##
## LEF for PtnCells ;
## created by Innovus v15.23-s045_1 on Wed Mar  4 17:17:28 2026
##

VERSION 5.8 ;

BUSBITCHARS "[]" ;
DIVIDERCHAR "/" ;

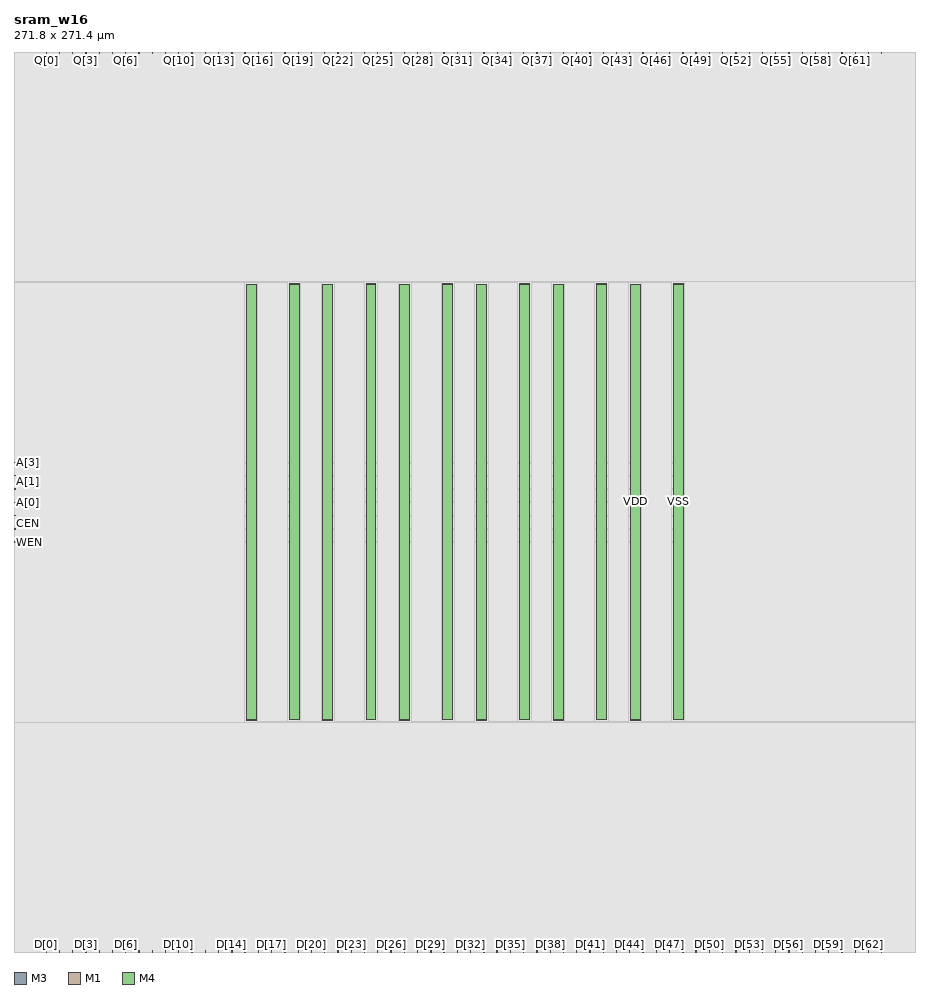
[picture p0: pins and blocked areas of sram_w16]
MACRO sram_w16
  CLASS BLOCK ;
  SIZE 271.8000 BY 271.4000 ;
  FOREIGN sram_w16 0.0000 0.0000 ;
  ORIGIN 0 0 ;
  SYMMETRY X Y R90 ;
  PIN CLK
    DIRECTION INPUT ;
    USE SIGNAL ;
    PORT
      LAYER M3 ;
        RECT 0.0000 127.5500 0.5200 127.6500 ;
    END
  END CLK
  PIN D[63]
    DIRECTION INPUT ;
    USE SIGNAL ;
    PORT
      LAYER M1 ;
        RECT 261.6500 0.0000 261.7500 0.5200 ;
    END
  END D[63]
  PIN D[62]
    DIRECTION INPUT ;
    USE SIGNAL ;
    PORT
      LAYER M1 ;
        RECT 257.6500 0.0000 257.7500 0.5200 ;
    END
  END D[62]
  PIN D[61]
    DIRECTION INPUT ;
    USE SIGNAL ;
    PORT
      LAYER M1 ;
        RECT 253.6500 0.0000 253.7500 0.5200 ;
    END
  END D[61]
  PIN D[60]
    DIRECTION INPUT ;
    USE SIGNAL ;
    PORT
      LAYER M1 ;
        RECT 249.6500 0.0000 249.7500 0.5200 ;
    END
  END D[60]
  PIN D[59]
    DIRECTION INPUT ;
    USE SIGNAL ;
    PORT
      LAYER M1 ;
        RECT 245.6500 0.0000 245.7500 0.5200 ;
    END
  END D[59]
  PIN D[58]
    DIRECTION INPUT ;
    USE SIGNAL ;
    PORT
      LAYER M1 ;
        RECT 241.6500 0.0000 241.7500 0.5200 ;
    END
  END D[58]
  PIN D[57]
    DIRECTION INPUT ;
    USE SIGNAL ;
    PORT
      LAYER M1 ;
        RECT 237.6500 0.0000 237.7500 0.5200 ;
    END
  END D[57]
  PIN D[56]
    DIRECTION INPUT ;
    USE SIGNAL ;
    PORT
      LAYER M1 ;
        RECT 233.6500 0.0000 233.7500 0.5200 ;
    END
  END D[56]
  PIN D[55]
    DIRECTION INPUT ;
    USE SIGNAL ;
    PORT
      LAYER M1 ;
        RECT 229.6500 0.0000 229.7500 0.5200 ;
    END
  END D[55]
  PIN D[54]
    DIRECTION INPUT ;
    USE SIGNAL ;
    PORT
      LAYER M1 ;
        RECT 225.6500 0.0000 225.7500 0.5200 ;
    END
  END D[54]
  PIN D[53]
    DIRECTION INPUT ;
    USE SIGNAL ;
    PORT
      LAYER M1 ;
        RECT 221.6500 0.0000 221.7500 0.5200 ;
    END
  END D[53]
  PIN D[52]
    DIRECTION INPUT ;
    USE SIGNAL ;
    PORT
      LAYER M1 ;
        RECT 217.6500 0.0000 217.7500 0.5200 ;
    END
  END D[52]
  PIN D[51]
    DIRECTION INPUT ;
    USE SIGNAL ;
    PORT
      LAYER M1 ;
        RECT 213.6500 0.0000 213.7500 0.5200 ;
    END
  END D[51]
  PIN D[50]
    DIRECTION INPUT ;
    USE SIGNAL ;
    PORT
      LAYER M1 ;
        RECT 209.6500 0.0000 209.7500 0.5200 ;
    END
  END D[50]
  PIN D[49]
    DIRECTION INPUT ;
    USE SIGNAL ;
    PORT
      LAYER M1 ;
        RECT 205.6500 0.0000 205.7500 0.5200 ;
    END
  END D[49]
  PIN D[48]
    DIRECTION INPUT ;
    USE SIGNAL ;
    PORT
      LAYER M1 ;
        RECT 201.6500 0.0000 201.7500 0.5200 ;
    END
  END D[48]
  PIN D[47]
    DIRECTION INPUT ;
    USE SIGNAL ;
    PORT
      LAYER M1 ;
        RECT 197.6500 0.0000 197.7500 0.5200 ;
    END
  END D[47]
  PIN D[46]
    DIRECTION INPUT ;
    USE SIGNAL ;
    PORT
      LAYER M1 ;
        RECT 193.6500 0.0000 193.7500 0.5200 ;
    END
  END D[46]
  PIN D[45]
    DIRECTION INPUT ;
    USE SIGNAL ;
    PORT
      LAYER M1 ;
        RECT 189.6500 0.0000 189.7500 0.5200 ;
    END
  END D[45]
  PIN D[44]
    DIRECTION INPUT ;
    USE SIGNAL ;
    PORT
      LAYER M1 ;
        RECT 185.6500 0.0000 185.7500 0.5200 ;
    END
  END D[44]
  PIN D[43]
    DIRECTION INPUT ;
    USE SIGNAL ;
    PORT
      LAYER M1 ;
        RECT 181.6500 0.0000 181.7500 0.5200 ;
    END
  END D[43]
  PIN D[42]
    DIRECTION INPUT ;
    USE SIGNAL ;
    PORT
      LAYER M1 ;
        RECT 177.6500 0.0000 177.7500 0.5200 ;
    END
  END D[42]
  PIN D[41]
    DIRECTION INPUT ;
    USE SIGNAL ;
    PORT
      LAYER M1 ;
        RECT 173.6500 0.0000 173.7500 0.5200 ;
    END
  END D[41]
  PIN D[40]
    DIRECTION INPUT ;
    USE SIGNAL ;
    PORT
      LAYER M1 ;
        RECT 169.6500 0.0000 169.7500 0.5200 ;
    END
  END D[40]
  PIN D[39]
    DIRECTION INPUT ;
    USE SIGNAL ;
    PORT
      LAYER M1 ;
        RECT 165.6500 0.0000 165.7500 0.5200 ;
    END
  END D[39]
  PIN D[38]
    DIRECTION INPUT ;
    USE SIGNAL ;
    PORT
      LAYER M1 ;
        RECT 161.6500 0.0000 161.7500 0.5200 ;
    END
  END D[38]
  PIN D[37]
    DIRECTION INPUT ;
    USE SIGNAL ;
    PORT
      LAYER M1 ;
        RECT 157.6500 0.0000 157.7500 0.5200 ;
    END
  END D[37]
  PIN D[36]
    DIRECTION INPUT ;
    USE SIGNAL ;
    PORT
      LAYER M1 ;
        RECT 153.6500 0.0000 153.7500 0.5200 ;
    END
  END D[36]
  PIN D[35]
    DIRECTION INPUT ;
    USE SIGNAL ;
    PORT
      LAYER M1 ;
        RECT 149.6500 0.0000 149.7500 0.5200 ;
    END
  END D[35]
  PIN D[34]
    DIRECTION INPUT ;
    USE SIGNAL ;
    PORT
      LAYER M1 ;
        RECT 145.6500 0.0000 145.7500 0.5200 ;
    END
  END D[34]
  PIN D[33]
    DIRECTION INPUT ;
    USE SIGNAL ;
    PORT
      LAYER M1 ;
        RECT 141.6500 0.0000 141.7500 0.5200 ;
    END
  END D[33]
  PIN D[32]
    DIRECTION INPUT ;
    USE SIGNAL ;
    PORT
      LAYER M1 ;
        RECT 137.6500 0.0000 137.7500 0.5200 ;
    END
  END D[32]
  PIN D[31]
    DIRECTION INPUT ;
    USE SIGNAL ;
    PORT
      LAYER M1 ;
        RECT 133.6500 0.0000 133.7500 0.5200 ;
    END
  END D[31]
  PIN D[30]
    DIRECTION INPUT ;
    USE SIGNAL ;
    PORT
      LAYER M1 ;
        RECT 129.6500 0.0000 129.7500 0.5200 ;
    END
  END D[30]
  PIN D[29]
    DIRECTION INPUT ;
    USE SIGNAL ;
    PORT
      LAYER M1 ;
        RECT 125.6500 0.0000 125.7500 0.5200 ;
    END
  END D[29]
  PIN D[28]
    DIRECTION INPUT ;
    USE SIGNAL ;
    PORT
      LAYER M1 ;
        RECT 121.6500 0.0000 121.7500 0.5200 ;
    END
  END D[28]
  PIN D[27]
    DIRECTION INPUT ;
    USE SIGNAL ;
    PORT
      LAYER M1 ;
        RECT 117.6500 0.0000 117.7500 0.5200 ;
    END
  END D[27]
  PIN D[26]
    DIRECTION INPUT ;
    USE SIGNAL ;
    PORT
      LAYER M1 ;
        RECT 113.6500 0.0000 113.7500 0.5200 ;
    END
  END D[26]
  PIN D[25]
    DIRECTION INPUT ;
    USE SIGNAL ;
    PORT
      LAYER M1 ;
        RECT 109.6500 0.0000 109.7500 0.5200 ;
    END
  END D[25]
  PIN D[24]
    DIRECTION INPUT ;
    USE SIGNAL ;
    PORT
      LAYER M1 ;
        RECT 105.6500 0.0000 105.7500 0.5200 ;
    END
  END D[24]
  PIN D[23]
    DIRECTION INPUT ;
    USE SIGNAL ;
    PORT
      LAYER M1 ;
        RECT 101.6500 0.0000 101.7500 0.5200 ;
    END
  END D[23]
  PIN D[22]
    DIRECTION INPUT ;
    USE SIGNAL ;
    PORT
      LAYER M1 ;
        RECT 97.6500 0.0000 97.7500 0.5200 ;
    END
  END D[22]
  PIN D[21]
    DIRECTION INPUT ;
    USE SIGNAL ;
    PORT
      LAYER M1 ;
        RECT 93.6500 0.0000 93.7500 0.5200 ;
    END
  END D[21]
  PIN D[20]
    DIRECTION INPUT ;
    USE SIGNAL ;
    PORT
      LAYER M1 ;
        RECT 89.6500 0.0000 89.7500 0.5200 ;
    END
  END D[20]
  PIN D[19]
    DIRECTION INPUT ;
    USE SIGNAL ;
    PORT
      LAYER M1 ;
        RECT 85.6500 0.0000 85.7500 0.5200 ;
    END
  END D[19]
  PIN D[18]
    DIRECTION INPUT ;
    USE SIGNAL ;
    PORT
      LAYER M1 ;
        RECT 81.6500 0.0000 81.7500 0.5200 ;
    END
  END D[18]
  PIN D[17]
    DIRECTION INPUT ;
    USE SIGNAL ;
    PORT
      LAYER M1 ;
        RECT 77.6500 0.0000 77.7500 0.5200 ;
    END
  END D[17]
  PIN D[16]
    DIRECTION INPUT ;
    USE SIGNAL ;
    PORT
      LAYER M1 ;
        RECT 73.6500 0.0000 73.7500 0.5200 ;
    END
  END D[16]
  PIN D[15]
    DIRECTION INPUT ;
    USE SIGNAL ;
    PORT
      LAYER M1 ;
        RECT 69.6500 0.0000 69.7500 0.5200 ;
    END
  END D[15]
  PIN D[14]
    DIRECTION INPUT ;
    USE SIGNAL ;
    PORT
      LAYER M1 ;
        RECT 65.6500 0.0000 65.7500 0.5200 ;
    END
  END D[14]
  PIN D[13]
    DIRECTION INPUT ;
    USE SIGNAL ;
    PORT
      LAYER M1 ;
        RECT 61.6500 0.0000 61.7500 0.5200 ;
    END
  END D[13]
  PIN D[12]
    DIRECTION INPUT ;
    USE SIGNAL ;
    PORT
      LAYER M1 ;
        RECT 57.6500 0.0000 57.7500 0.5200 ;
    END
  END D[12]
  PIN D[11]
    DIRECTION INPUT ;
    USE SIGNAL ;
    PORT
      LAYER M1 ;
        RECT 53.6500 0.0000 53.7500 0.5200 ;
    END
  END D[11]
  PIN D[10]
    DIRECTION INPUT ;
    USE SIGNAL ;
    PORT
      LAYER M1 ;
        RECT 49.6500 0.0000 49.7500 0.5200 ;
    END
  END D[10]
  PIN D[9]
    DIRECTION INPUT ;
    USE SIGNAL ;
    PORT
      LAYER M1 ;
        RECT 45.6500 0.0000 45.7500 0.5200 ;
    END
  END D[9]
  PIN D[8]
    DIRECTION INPUT ;
    USE SIGNAL ;
    PORT
      LAYER M1 ;
        RECT 41.6500 0.0000 41.7500 0.5200 ;
    END
  END D[8]
  PIN D[7]
    DIRECTION INPUT ;
    USE SIGNAL ;
    PORT
      LAYER M1 ;
        RECT 37.6500 0.0000 37.7500 0.5200 ;
    END
  END D[7]
  PIN D[6]
    DIRECTION INPUT ;
    USE SIGNAL ;
    PORT
      LAYER M1 ;
        RECT 33.6500 0.0000 33.7500 0.5200 ;
    END
  END D[6]
  PIN D[5]
    DIRECTION INPUT ;
    USE SIGNAL ;
    PORT
      LAYER M1 ;
        RECT 29.6500 0.0000 29.7500 0.5200 ;
    END
  END D[5]
  PIN D[4]
    DIRECTION INPUT ;
    USE SIGNAL ;
    PORT
      LAYER M1 ;
        RECT 25.6500 0.0000 25.7500 0.5200 ;
    END
  END D[4]
  PIN D[3]
    DIRECTION INPUT ;
    USE SIGNAL ;
    PORT
      LAYER M1 ;
        RECT 21.6500 0.0000 21.7500 0.5200 ;
    END
  END D[3]
  PIN D[2]
    DIRECTION INPUT ;
    USE SIGNAL ;
    PORT
      LAYER M1 ;
        RECT 17.6500 0.0000 17.7500 0.5200 ;
    END
  END D[2]
  PIN D[1]
    DIRECTION INPUT ;
    USE SIGNAL ;
    PORT
      LAYER M1 ;
        RECT 13.6500 0.0000 13.7500 0.5200 ;
    END
  END D[1]
  PIN D[0]
    DIRECTION INPUT ;
    USE SIGNAL ;
    PORT
      LAYER M1 ;
        RECT 9.6500 0.0000 9.7500 0.5200 ;
    END
  END D[0]
  PIN Q[63]
    DIRECTION OUTPUT ;
    USE SIGNAL ;
    PORT
      LAYER M1 ;
        RECT 261.6550 270.9300 261.7450 271.4000 ;
    END
  END Q[63]
  PIN Q[62]
    DIRECTION OUTPUT ;
    USE SIGNAL ;
    PORT
      LAYER M1 ;
        RECT 257.6550 270.9300 257.7450 271.4000 ;
    END
  END Q[62]
  PIN Q[61]
    DIRECTION OUTPUT ;
    USE SIGNAL ;
    PORT
      LAYER M1 ;
        RECT 253.6550 270.9300 253.7450 271.4000 ;
    END
  END Q[61]
  PIN Q[60]
    DIRECTION OUTPUT ;
    USE SIGNAL ;
    PORT
      LAYER M1 ;
        RECT 249.6550 270.9300 249.7450 271.4000 ;
    END
  END Q[60]
  PIN Q[59]
    DIRECTION OUTPUT ;
    USE SIGNAL ;
    PORT
      LAYER M1 ;
        RECT 245.6550 270.9300 245.7450 271.4000 ;
    END
  END Q[59]
  PIN Q[58]
    DIRECTION OUTPUT ;
    USE SIGNAL ;
    PORT
      LAYER M1 ;
        RECT 241.6550 270.9300 241.7450 271.4000 ;
    END
  END Q[58]
  PIN Q[57]
    DIRECTION OUTPUT ;
    USE SIGNAL ;
    PORT
      LAYER M1 ;
        RECT 237.6550 270.9300 237.7450 271.4000 ;
    END
  END Q[57]
  PIN Q[56]
    DIRECTION OUTPUT ;
    USE SIGNAL ;
    PORT
      LAYER M1 ;
        RECT 233.6550 270.9300 233.7450 271.4000 ;
    END
  END Q[56]
  PIN Q[55]
    DIRECTION OUTPUT ;
    USE SIGNAL ;
    PORT
      LAYER M1 ;
        RECT 229.6550 270.9300 229.7450 271.4000 ;
    END
  END Q[55]
  PIN Q[54]
    DIRECTION OUTPUT ;
    USE SIGNAL ;
    PORT
      LAYER M1 ;
        RECT 225.6550 270.9300 225.7450 271.4000 ;
    END
  END Q[54]
  PIN Q[53]
    DIRECTION OUTPUT ;
    USE SIGNAL ;
    PORT
      LAYER M1 ;
        RECT 221.6550 270.9300 221.7450 271.4000 ;
    END
  END Q[53]
  PIN Q[52]
    DIRECTION OUTPUT ;
    USE SIGNAL ;
    PORT
      LAYER M1 ;
        RECT 217.6550 270.9300 217.7450 271.4000 ;
    END
  END Q[52]
  PIN Q[51]
    DIRECTION OUTPUT ;
    USE SIGNAL ;
    PORT
      LAYER M1 ;
        RECT 213.6550 270.9300 213.7450 271.4000 ;
    END
  END Q[51]
  PIN Q[50]
    DIRECTION OUTPUT ;
    USE SIGNAL ;
    PORT
      LAYER M1 ;
        RECT 209.6550 270.9300 209.7450 271.4000 ;
    END
  END Q[50]
  PIN Q[49]
    DIRECTION OUTPUT ;
    USE SIGNAL ;
    PORT
      LAYER M1 ;
        RECT 205.6550 270.9300 205.7450 271.4000 ;
    END
  END Q[49]
  PIN Q[48]
    DIRECTION OUTPUT ;
    USE SIGNAL ;
    PORT
      LAYER M1 ;
        RECT 201.6550 270.9300 201.7450 271.4000 ;
    END
  END Q[48]
  PIN Q[47]
    DIRECTION OUTPUT ;
    USE SIGNAL ;
    PORT
      LAYER M1 ;
        RECT 197.6550 270.9300 197.7450 271.4000 ;
    END
  END Q[47]
  PIN Q[46]
    DIRECTION OUTPUT ;
    USE SIGNAL ;
    PORT
      LAYER M1 ;
        RECT 193.6550 270.9300 193.7450 271.4000 ;
    END
  END Q[46]
  PIN Q[45]
    DIRECTION OUTPUT ;
    USE SIGNAL ;
    PORT
      LAYER M1 ;
        RECT 189.6550 270.9300 189.7450 271.4000 ;
    END
  END Q[45]
  PIN Q[44]
    DIRECTION OUTPUT ;
    USE SIGNAL ;
    PORT
      LAYER M1 ;
        RECT 185.6550 270.9300 185.7450 271.4000 ;
    END
  END Q[44]
  PIN Q[43]
    DIRECTION OUTPUT ;
    USE SIGNAL ;
    PORT
      LAYER M1 ;
        RECT 181.6550 270.9300 181.7450 271.4000 ;
    END
  END Q[43]
  PIN Q[42]
    DIRECTION OUTPUT ;
    USE SIGNAL ;
    PORT
      LAYER M1 ;
        RECT 177.6550 270.9300 177.7450 271.4000 ;
    END
  END Q[42]
  PIN Q[41]
    DIRECTION OUTPUT ;
    USE SIGNAL ;
    PORT
      LAYER M1 ;
        RECT 173.6550 270.9300 173.7450 271.4000 ;
    END
  END Q[41]
  PIN Q[40]
    DIRECTION OUTPUT ;
    USE SIGNAL ;
    PORT
      LAYER M1 ;
        RECT 169.6550 270.9300 169.7450 271.4000 ;
    END
  END Q[40]
  PIN Q[39]
    DIRECTION OUTPUT ;
    USE SIGNAL ;
    PORT
      LAYER M1 ;
        RECT 165.6550 270.9300 165.7450 271.4000 ;
    END
  END Q[39]
  PIN Q[38]
    DIRECTION OUTPUT ;
    USE SIGNAL ;
    PORT
      LAYER M1 ;
        RECT 161.6550 270.9300 161.7450 271.4000 ;
    END
  END Q[38]
  PIN Q[37]
    DIRECTION OUTPUT ;
    USE SIGNAL ;
    PORT
      LAYER M1 ;
        RECT 157.6550 270.9300 157.7450 271.4000 ;
    END
  END Q[37]
  PIN Q[36]
    DIRECTION OUTPUT ;
    USE SIGNAL ;
    PORT
      LAYER M1 ;
        RECT 153.6550 270.9300 153.7450 271.4000 ;
    END
  END Q[36]
  PIN Q[35]
    DIRECTION OUTPUT ;
    USE SIGNAL ;
    PORT
      LAYER M1 ;
        RECT 149.6550 270.9300 149.7450 271.4000 ;
    END
  END Q[35]
  PIN Q[34]
    DIRECTION OUTPUT ;
    USE SIGNAL ;
    PORT
      LAYER M1 ;
        RECT 145.6550 270.9300 145.7450 271.4000 ;
    END
  END Q[34]
  PIN Q[33]
    DIRECTION OUTPUT ;
    USE SIGNAL ;
    PORT
      LAYER M1 ;
        RECT 141.6550 270.9300 141.7450 271.4000 ;
    END
  END Q[33]
  PIN Q[32]
    DIRECTION OUTPUT ;
    USE SIGNAL ;
    PORT
      LAYER M1 ;
        RECT 137.6550 270.9300 137.7450 271.4000 ;
    END
  END Q[32]
  PIN Q[31]
    DIRECTION OUTPUT ;
    USE SIGNAL ;
    PORT
      LAYER M1 ;
        RECT 133.6550 270.9300 133.7450 271.4000 ;
    END
  END Q[31]
  PIN Q[30]
    DIRECTION OUTPUT ;
    USE SIGNAL ;
    PORT
      LAYER M1 ;
        RECT 129.6550 270.9300 129.7450 271.4000 ;
    END
  END Q[30]
  PIN Q[29]
    DIRECTION OUTPUT ;
    USE SIGNAL ;
    PORT
      LAYER M1 ;
        RECT 125.6550 270.9300 125.7450 271.4000 ;
    END
  END Q[29]
  PIN Q[28]
    DIRECTION OUTPUT ;
    USE SIGNAL ;
    PORT
      LAYER M1 ;
        RECT 121.6550 270.9300 121.7450 271.4000 ;
    END
  END Q[28]
  PIN Q[27]
    DIRECTION OUTPUT ;
    USE SIGNAL ;
    PORT
      LAYER M1 ;
        RECT 117.6550 270.9300 117.7450 271.4000 ;
    END
  END Q[27]
  PIN Q[26]
    DIRECTION OUTPUT ;
    USE SIGNAL ;
    PORT
      LAYER M1 ;
        RECT 113.6550 270.9300 113.7450 271.4000 ;
    END
  END Q[26]
  PIN Q[25]
    DIRECTION OUTPUT ;
    USE SIGNAL ;
    PORT
      LAYER M1 ;
        RECT 109.6550 270.9300 109.7450 271.4000 ;
    END
  END Q[25]
  PIN Q[24]
    DIRECTION OUTPUT ;
    USE SIGNAL ;
    PORT
      LAYER M1 ;
        RECT 105.6550 270.9300 105.7450 271.4000 ;
    END
  END Q[24]
  PIN Q[23]
    DIRECTION OUTPUT ;
    USE SIGNAL ;
    PORT
      LAYER M1 ;
        RECT 101.6550 270.9300 101.7450 271.4000 ;
    END
  END Q[23]
  PIN Q[22]
    DIRECTION OUTPUT ;
    USE SIGNAL ;
    PORT
      LAYER M1 ;
        RECT 97.6550 270.9300 97.7450 271.4000 ;
    END
  END Q[22]
  PIN Q[21]
    DIRECTION OUTPUT ;
    USE SIGNAL ;
    PORT
      LAYER M1 ;
        RECT 93.6550 270.9300 93.7450 271.4000 ;
    END
  END Q[21]
  PIN Q[20]
    DIRECTION OUTPUT ;
    USE SIGNAL ;
    PORT
      LAYER M1 ;
        RECT 89.6550 270.9300 89.7450 271.4000 ;
    END
  END Q[20]
  PIN Q[19]
    DIRECTION OUTPUT ;
    USE SIGNAL ;
    PORT
      LAYER M1 ;
        RECT 85.6550 270.9300 85.7450 271.4000 ;
    END
  END Q[19]
  PIN Q[18]
    DIRECTION OUTPUT ;
    USE SIGNAL ;
    PORT
      LAYER M1 ;
        RECT 81.6550 270.9300 81.7450 271.4000 ;
    END
  END Q[18]
  PIN Q[17]
    DIRECTION OUTPUT ;
    USE SIGNAL ;
    PORT
      LAYER M1 ;
        RECT 77.6550 270.9300 77.7450 271.4000 ;
    END
  END Q[17]
  PIN Q[16]
    DIRECTION OUTPUT ;
    USE SIGNAL ;
    PORT
      LAYER M1 ;
        RECT 73.6550 270.9300 73.7450 271.4000 ;
    END
  END Q[16]
  PIN Q[15]
    DIRECTION OUTPUT ;
    USE SIGNAL ;
    PORT
      LAYER M1 ;
        RECT 69.6550 270.9300 69.7450 271.4000 ;
    END
  END Q[15]
  PIN Q[14]
    DIRECTION OUTPUT ;
    USE SIGNAL ;
    PORT
      LAYER M1 ;
        RECT 65.6550 270.9300 65.7450 271.4000 ;
    END
  END Q[14]
  PIN Q[13]
    DIRECTION OUTPUT ;
    USE SIGNAL ;
    PORT
      LAYER M1 ;
        RECT 61.6550 270.9300 61.7450 271.4000 ;
    END
  END Q[13]
  PIN Q[12]
    DIRECTION OUTPUT ;
    USE SIGNAL ;
    PORT
      LAYER M1 ;
        RECT 57.6550 270.9300 57.7450 271.4000 ;
    END
  END Q[12]
  PIN Q[11]
    DIRECTION OUTPUT ;
    USE SIGNAL ;
    PORT
      LAYER M1 ;
        RECT 53.6550 270.9300 53.7450 271.4000 ;
    END
  END Q[11]
  PIN Q[10]
    DIRECTION OUTPUT ;
    USE SIGNAL ;
    PORT
      LAYER M1 ;
        RECT 49.6550 270.9300 49.7450 271.4000 ;
    END
  END Q[10]
  PIN Q[9]
    DIRECTION OUTPUT ;
    USE SIGNAL ;
    PORT
      LAYER M1 ;
        RECT 45.6550 270.9300 45.7450 271.4000 ;
    END
  END Q[9]
  PIN Q[8]
    DIRECTION OUTPUT ;
    USE SIGNAL ;
    PORT
      LAYER M1 ;
        RECT 41.6550 270.9300 41.7450 271.4000 ;
    END
  END Q[8]
  PIN Q[7]
    DIRECTION OUTPUT ;
    USE SIGNAL ;
    PORT
      LAYER M1 ;
        RECT 37.6550 270.9300 37.7450 271.4000 ;
    END
  END Q[7]
  PIN Q[6]
    DIRECTION OUTPUT ;
    USE SIGNAL ;
    PORT
      LAYER M1 ;
        RECT 33.6550 270.9300 33.7450 271.4000 ;
    END
  END Q[6]
  PIN Q[5]
    DIRECTION OUTPUT ;
    USE SIGNAL ;
    PORT
      LAYER M1 ;
        RECT 29.6550 270.9300 29.7450 271.4000 ;
    END
  END Q[5]
  PIN Q[4]
    DIRECTION OUTPUT ;
    USE SIGNAL ;
    PORT
      LAYER M1 ;
        RECT 25.6550 270.9300 25.7450 271.4000 ;
    END
  END Q[4]
  PIN Q[3]
    DIRECTION OUTPUT ;
    USE SIGNAL ;
    PORT
      LAYER M1 ;
        RECT 21.6550 270.9300 21.7450 271.4000 ;
    END
  END Q[3]
  PIN Q[2]
    DIRECTION OUTPUT ;
    USE SIGNAL ;
    PORT
      LAYER M1 ;
        RECT 17.6550 270.9300 17.7450 271.4000 ;
    END
  END Q[2]
  PIN Q[1]
    DIRECTION OUTPUT ;
    USE SIGNAL ;
    PORT
      LAYER M1 ;
        RECT 13.6550 270.9300 13.7450 271.4000 ;
    END
  END Q[1]
  PIN Q[0]
    DIRECTION OUTPUT ;
    USE SIGNAL ;
    PORT
      LAYER M1 ;
        RECT 9.6550 270.9300 9.7450 271.4000 ;
    END
  END Q[0]
  PIN CEN
    DIRECTION INPUT ;
    USE SIGNAL ;
    PORT
      LAYER M3 ;
        RECT 0.0000 131.5500 0.5200 131.6500 ;
    END
  END CEN
  PIN WEN
    DIRECTION INPUT ;
    USE SIGNAL ;
    PORT
      LAYER M3 ;
        RECT 0.0000 123.5500 0.5200 123.6500 ;
    END
  END WEN
  PIN A[3]
    DIRECTION INPUT ;
    USE SIGNAL ;
    PORT
      LAYER M3 ;
        RECT 0.0000 147.5500 0.5200 147.6500 ;
    END
  END A[3]
  PIN A[2]
    DIRECTION INPUT ;
    USE SIGNAL ;
    PORT
      LAYER M3 ;
        RECT 0.0000 143.5500 0.5200 143.6500 ;
    END
  END A[2]
  PIN A[1]
    DIRECTION INPUT ;
    USE SIGNAL ;
    PORT
      LAYER M3 ;
        RECT 0.0000 139.5500 0.5200 139.6500 ;
    END
  END A[1]
  PIN A[0]
    DIRECTION INPUT ;
    USE SIGNAL ;
    PORT
      LAYER M3 ;
        RECT 0.0000 135.5500 0.5200 135.6500 ;
    END
  END A[0]
  PIN VSS
    DIRECTION INOUT ;
    USE GROUND ;

# P/G power stripe data as pin
    PORT
      LAYER M4 ;
        RECT 198.8000 70.0000 201.8000 201.4000 ;
        RECT 175.6400 70.0000 178.6400 201.4000 ;
        RECT 152.4800 70.0000 155.4800 201.4000 ;
        RECT 129.3200 70.0000 132.3200 201.4000 ;
        RECT 106.1600 70.0000 109.1600 201.4000 ;
        RECT 83.0000 70.0000 86.0000 201.4000 ;
        RECT 83.0000 201.2350 86.0000 201.5650 ;
        RECT 106.1600 201.2350 109.1600 201.5650 ;
        RECT 129.3200 201.2350 132.3200 201.5650 ;
        RECT 152.4800 201.2350 155.4800 201.5650 ;
        RECT 175.6400 201.2350 178.6400 201.5650 ;
        RECT 198.8000 201.2350 201.8000 201.5650 ;
    END
# end of P/G power stripe data as pin

  END VSS
  PIN VDD
    DIRECTION INOUT ;
    USE POWER ;

# P/G power stripe data as pin
    PORT
      LAYER M4 ;
        RECT 185.8000 70.0000 188.8000 201.4000 ;
        RECT 162.6400 70.0000 165.6400 201.4000 ;
        RECT 139.4800 70.0000 142.4800 201.4000 ;
        RECT 116.3200 70.0000 119.3200 201.4000 ;
        RECT 93.1600 70.0000 96.1600 201.4000 ;
        RECT 70.0000 70.0000 73.0000 201.4000 ;
        RECT 70.0000 69.8350 73.0000 70.1650 ;
        RECT 93.1600 69.8350 96.1600 70.1650 ;
        RECT 116.3200 69.8350 119.3200 70.1650 ;
        RECT 139.4800 69.8350 142.4800 70.1650 ;
        RECT 162.6400 69.8350 165.6400 70.1650 ;
        RECT 185.8000 69.8350 188.8000 70.1650 ;
    END
# end of P/G power stripe data as pin

  END VDD
  OBS
    LAYER M1 ;
      RECT 261.9050 270.7700 271.8000 271.4000 ;
      RECT 257.9050 270.7700 261.4950 271.4000 ;
      RECT 253.9050 270.7700 257.4950 271.4000 ;
      RECT 249.9050 270.7700 253.4950 271.4000 ;
      RECT 245.9050 270.7700 249.4950 271.4000 ;
      RECT 241.9050 270.7700 245.4950 271.4000 ;
      RECT 237.9050 270.7700 241.4950 271.4000 ;
      RECT 233.9050 270.7700 237.4950 271.4000 ;
      RECT 229.9050 270.7700 233.4950 271.4000 ;
      RECT 225.9050 270.7700 229.4950 271.4000 ;
      RECT 221.9050 270.7700 225.4950 271.4000 ;
      RECT 217.9050 270.7700 221.4950 271.4000 ;
      RECT 213.9050 270.7700 217.4950 271.4000 ;
      RECT 209.9050 270.7700 213.4950 271.4000 ;
      RECT 205.9050 270.7700 209.4950 271.4000 ;
      RECT 201.9050 270.7700 205.4950 271.4000 ;
      RECT 197.9050 270.7700 201.4950 271.4000 ;
      RECT 193.9050 270.7700 197.4950 271.4000 ;
      RECT 189.9050 270.7700 193.4950 271.4000 ;
      RECT 185.9050 270.7700 189.4950 271.4000 ;
      RECT 181.9050 270.7700 185.4950 271.4000 ;
      RECT 177.9050 270.7700 181.4950 271.4000 ;
      RECT 173.9050 270.7700 177.4950 271.4000 ;
      RECT 169.9050 270.7700 173.4950 271.4000 ;
      RECT 165.9050 270.7700 169.4950 271.4000 ;
      RECT 161.9050 270.7700 165.4950 271.4000 ;
      RECT 157.9050 270.7700 161.4950 271.4000 ;
      RECT 153.9050 270.7700 157.4950 271.4000 ;
      RECT 149.9050 270.7700 153.4950 271.4000 ;
      RECT 145.9050 270.7700 149.4950 271.4000 ;
      RECT 141.9050 270.7700 145.4950 271.4000 ;
      RECT 137.9050 270.7700 141.4950 271.4000 ;
      RECT 133.9050 270.7700 137.4950 271.4000 ;
      RECT 129.9050 270.7700 133.4950 271.4000 ;
      RECT 125.9050 270.7700 129.4950 271.4000 ;
      RECT 121.9050 270.7700 125.4950 271.4000 ;
      RECT 117.9050 270.7700 121.4950 271.4000 ;
      RECT 113.9050 270.7700 117.4950 271.4000 ;
      RECT 109.9050 270.7700 113.4950 271.4000 ;
      RECT 105.9050 270.7700 109.4950 271.4000 ;
      RECT 101.9050 270.7700 105.4950 271.4000 ;
      RECT 97.9050 270.7700 101.4950 271.4000 ;
      RECT 93.9050 270.7700 97.4950 271.4000 ;
      RECT 89.9050 270.7700 93.4950 271.4000 ;
      RECT 85.9050 270.7700 89.4950 271.4000 ;
      RECT 81.9050 270.7700 85.4950 271.4000 ;
      RECT 77.9050 270.7700 81.4950 271.4000 ;
      RECT 73.9050 270.7700 77.4950 271.4000 ;
      RECT 69.9050 270.7700 73.4950 271.4000 ;
      RECT 65.9050 270.7700 69.4950 271.4000 ;
      RECT 61.9050 270.7700 65.4950 271.4000 ;
      RECT 57.9050 270.7700 61.4950 271.4000 ;
      RECT 53.9050 270.7700 57.4950 271.4000 ;
      RECT 49.9050 270.7700 53.4950 271.4000 ;
      RECT 45.9050 270.7700 49.4950 271.4000 ;
      RECT 41.9050 270.7700 45.4950 271.4000 ;
      RECT 37.9050 270.7700 41.4950 271.4000 ;
      RECT 33.9050 270.7700 37.4950 271.4000 ;
      RECT 29.9050 270.7700 33.4950 271.4000 ;
      RECT 25.9050 270.7700 29.4950 271.4000 ;
      RECT 21.9050 270.7700 25.4950 271.4000 ;
      RECT 17.9050 270.7700 21.4950 271.4000 ;
      RECT 13.9050 270.7700 17.4950 271.4000 ;
      RECT 9.9050 270.7700 13.4950 271.4000 ;
      RECT 0.0000 270.7700 9.4950 271.4000 ;
      RECT 0.0000 0.6800 271.8000 270.7700 ;
      RECT 261.9100 0.0000 271.8000 0.6800 ;
      RECT 257.9100 0.0000 261.4900 0.6800 ;
      RECT 253.9100 0.0000 257.4900 0.6800 ;
      RECT 249.9100 0.0000 253.4900 0.6800 ;
      RECT 245.9100 0.0000 249.4900 0.6800 ;
      RECT 241.9100 0.0000 245.4900 0.6800 ;
      RECT 237.9100 0.0000 241.4900 0.6800 ;
      RECT 233.9100 0.0000 237.4900 0.6800 ;
      RECT 229.9100 0.0000 233.4900 0.6800 ;
      RECT 225.9100 0.0000 229.4900 0.6800 ;
      RECT 221.9100 0.0000 225.4900 0.6800 ;
      RECT 217.9100 0.0000 221.4900 0.6800 ;
      RECT 213.9100 0.0000 217.4900 0.6800 ;
      RECT 209.9100 0.0000 213.4900 0.6800 ;
      RECT 205.9100 0.0000 209.4900 0.6800 ;
      RECT 201.9100 0.0000 205.4900 0.6800 ;
      RECT 197.9100 0.0000 201.4900 0.6800 ;
      RECT 193.9100 0.0000 197.4900 0.6800 ;
      RECT 189.9100 0.0000 193.4900 0.6800 ;
      RECT 185.9100 0.0000 189.4900 0.6800 ;
      RECT 181.9100 0.0000 185.4900 0.6800 ;
      RECT 177.9100 0.0000 181.4900 0.6800 ;
      RECT 173.9100 0.0000 177.4900 0.6800 ;
      RECT 169.9100 0.0000 173.4900 0.6800 ;
      RECT 165.9100 0.0000 169.4900 0.6800 ;
      RECT 161.9100 0.0000 165.4900 0.6800 ;
      RECT 157.9100 0.0000 161.4900 0.6800 ;
      RECT 153.9100 0.0000 157.4900 0.6800 ;
      RECT 149.9100 0.0000 153.4900 0.6800 ;
      RECT 145.9100 0.0000 149.4900 0.6800 ;
      RECT 141.9100 0.0000 145.4900 0.6800 ;
      RECT 137.9100 0.0000 141.4900 0.6800 ;
      RECT 133.9100 0.0000 137.4900 0.6800 ;
      RECT 129.9100 0.0000 133.4900 0.6800 ;
      RECT 125.9100 0.0000 129.4900 0.6800 ;
      RECT 121.9100 0.0000 125.4900 0.6800 ;
      RECT 117.9100 0.0000 121.4900 0.6800 ;
      RECT 113.9100 0.0000 117.4900 0.6800 ;
      RECT 109.9100 0.0000 113.4900 0.6800 ;
      RECT 105.9100 0.0000 109.4900 0.6800 ;
      RECT 101.9100 0.0000 105.4900 0.6800 ;
      RECT 97.9100 0.0000 101.4900 0.6800 ;
      RECT 93.9100 0.0000 97.4900 0.6800 ;
      RECT 89.9100 0.0000 93.4900 0.6800 ;
      RECT 85.9100 0.0000 89.4900 0.6800 ;
      RECT 81.9100 0.0000 85.4900 0.6800 ;
      RECT 77.9100 0.0000 81.4900 0.6800 ;
      RECT 73.9100 0.0000 77.4900 0.6800 ;
      RECT 69.9100 0.0000 73.4900 0.6800 ;
      RECT 65.9100 0.0000 69.4900 0.6800 ;
      RECT 61.9100 0.0000 65.4900 0.6800 ;
      RECT 57.9100 0.0000 61.4900 0.6800 ;
      RECT 53.9100 0.0000 57.4900 0.6800 ;
      RECT 49.9100 0.0000 53.4900 0.6800 ;
      RECT 45.9100 0.0000 49.4900 0.6800 ;
      RECT 41.9100 0.0000 45.4900 0.6800 ;
      RECT 37.9100 0.0000 41.4900 0.6800 ;
      RECT 33.9100 0.0000 37.4900 0.6800 ;
      RECT 29.9100 0.0000 33.4900 0.6800 ;
      RECT 25.9100 0.0000 29.4900 0.6800 ;
      RECT 21.9100 0.0000 25.4900 0.6800 ;
      RECT 17.9100 0.0000 21.4900 0.6800 ;
      RECT 13.9100 0.0000 17.4900 0.6800 ;
      RECT 9.9100 0.0000 13.4900 0.6800 ;
      RECT 0.0000 0.0000 9.4900 0.6800 ;
    LAYER M2 ;
      RECT 0.0000 0.0000 271.8000 271.4000 ;
    LAYER M3 ;
      RECT 0.0000 147.7500 271.8000 271.4000 ;
      RECT 0.6200 147.4500 271.8000 147.7500 ;
      RECT 0.0000 143.7500 271.8000 147.4500 ;
      RECT 0.6200 143.4500 271.8000 143.7500 ;
      RECT 0.0000 139.7500 271.8000 143.4500 ;
      RECT 0.6200 139.4500 271.8000 139.7500 ;
      RECT 0.0000 135.7500 271.8000 139.4500 ;
      RECT 0.6200 135.4500 271.8000 135.7500 ;
      RECT 0.0000 131.7500 271.8000 135.4500 ;
      RECT 0.6200 131.4500 271.8000 131.7500 ;
      RECT 0.0000 127.7500 271.8000 131.4500 ;
      RECT 0.6200 127.4500 271.8000 127.7500 ;
      RECT 0.0000 123.7500 271.8000 127.4500 ;
      RECT 0.6200 123.4500 271.8000 123.7500 ;
      RECT 0.0000 0.0000 271.8000 123.4500 ;
    LAYER M4 ;
      RECT 0.0000 202.0650 271.8000 271.4000 ;
      RECT 179.1400 201.9000 198.3000 202.0650 ;
      RECT 155.9800 201.9000 175.1400 202.0650 ;
      RECT 132.8200 201.9000 151.9800 202.0650 ;
      RECT 109.6600 201.9000 128.8200 202.0650 ;
      RECT 86.5000 201.9000 105.6600 202.0650 ;
      RECT 0.0000 201.9000 82.5000 202.0650 ;
      RECT 202.3000 69.5000 271.8000 202.0650 ;
      RECT 189.3000 69.5000 198.3000 201.9000 ;
      RECT 179.1400 69.5000 185.3000 201.9000 ;
      RECT 166.1400 69.5000 175.1400 201.9000 ;
      RECT 155.9800 69.5000 162.1400 201.9000 ;
      RECT 142.9800 69.5000 151.9800 201.9000 ;
      RECT 132.8200 69.5000 138.9800 201.9000 ;
      RECT 119.8200 69.5000 128.8200 201.9000 ;
      RECT 109.6600 69.5000 115.8200 201.9000 ;
      RECT 96.6600 69.5000 105.6600 201.9000 ;
      RECT 86.5000 69.5000 92.6600 201.9000 ;
      RECT 73.5000 69.5000 82.5000 201.9000 ;
      RECT 189.3000 69.3350 271.8000 69.5000 ;
      RECT 166.1400 69.3350 185.3000 69.5000 ;
      RECT 142.9800 69.3350 162.1400 69.5000 ;
      RECT 119.8200 69.3350 138.9800 69.5000 ;
      RECT 96.6600 69.3350 115.8200 69.5000 ;
      RECT 73.5000 69.3350 92.6600 69.5000 ;
      RECT 0.0000 69.3350 69.5000 201.9000 ;
      RECT 0.0000 0.0000 271.8000 69.3350 ;
  END
END sram_w16

END LIBRARY
